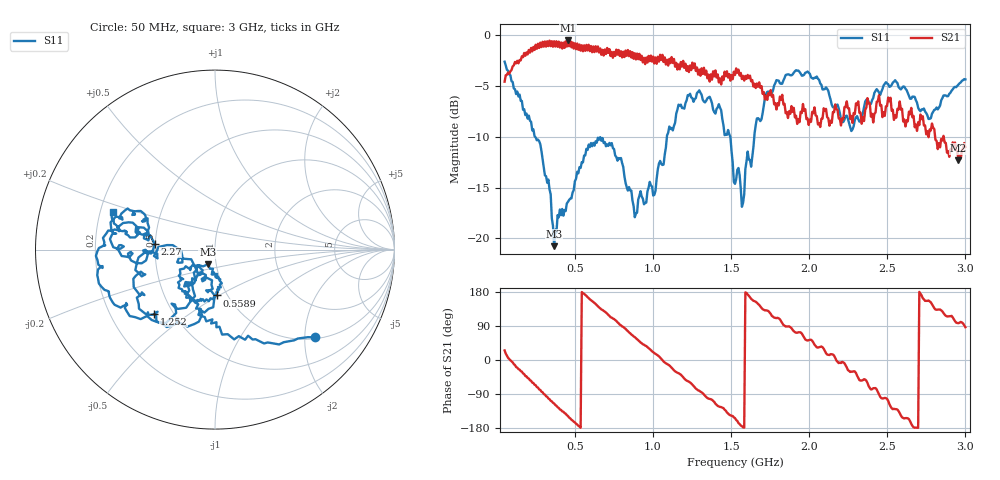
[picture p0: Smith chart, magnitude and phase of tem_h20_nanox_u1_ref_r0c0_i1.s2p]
! nanovna_capture.py 2026-10-26T21:48:21+0900
! NanoVNA-F_V2 fw 0.6.0 SN 4A3639384505514B
! cal: load open short thru cal'ed  over 50000000-3000000000 Hz, 201 points
! points 401, avg 4
! TEM h=20, genuine Nano X, 0 deg, centred, interleaved run G1
# HZ S RI R 50
! S12 and S22 are not measured (written as 0)
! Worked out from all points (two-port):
!   401 points, 50 MHz to 3 GHz, reference 50 ohm
!   highest |S21| = -0.49 dB at 455.6 MHz (marker M1); lowest = -12.3 dB at 2.956 GHz (marker M2)
!   |S21| within 3 dB of the highest: 89.33 MHz to 1.229 GHz (1.139 GHz wide, 173 % of centre); 1.231 GHz to 1.274 GHz (42.91 MHz wide, 3.43 % of centre) (the widest 2 of 10)
!   lowest |S11| = -20.8 dB at 367.1 MHz (marker M3), VSWR 1.20, Z = 45.5 - j7.54 ohm
!   |S11| at or under -10 dB: 245.4 MHz to 1.089 GHz (843.6 MHz wide, 126 % of centre); 1.495 GHz to 1.648 GHz (153.2 MHz wide, 9.75 % of centre)
!   S12 and S22 are empty: the file has one direction only
!   S11 on the Smith chart (normalised r, x): 50 MHz: 1.04, -2.25; 558.9 MHz: 0.89, -0.49; 1.252 GHz: 0.40, -0.37; 2.27 GHz: 0.50, +0.04; 3 GHz: 0.25, +0.17
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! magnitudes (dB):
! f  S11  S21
! 50 MHz  -2.6  -4.6
! 278.6 MHz  -10.7  -0.7
! 367.1 MHz  -20.8  -0.6
! 455.6 MHz  -16.4  -0.5
! 544.1 MHz  -12.5  -1.0
! 558.9 MHz  -11.8  -1.0
! 735.9 MHz  -10.6  -1.6
! 883.4 MHz  -17.9  -1.7
! 1.009 GHz  -15.7  -2.8
! 1.038 GHz  -12.6  -2.6
! 1.164 GHz  -6.8  -2.9
! 1.252 GHz  -6.2  -2.7
! 1.429 GHz  -7.1  -4.2
! 1.525 GHz  -14.6  -3.9
! 1.577 GHz  -16.5  -4.0
! 1.732 GHz  -5.6  -6.3
! 2.019 GHz  -4.2  -7.5
! 2.27 GHz  -9.4  -7.9
! 2.513 GHz  -5.1  -6.5
! 2.771 GHz  -8.2  -9.3
! 2.956 GHz  -4.8  -12.3
! 3 GHz  -4.3  -11.0
